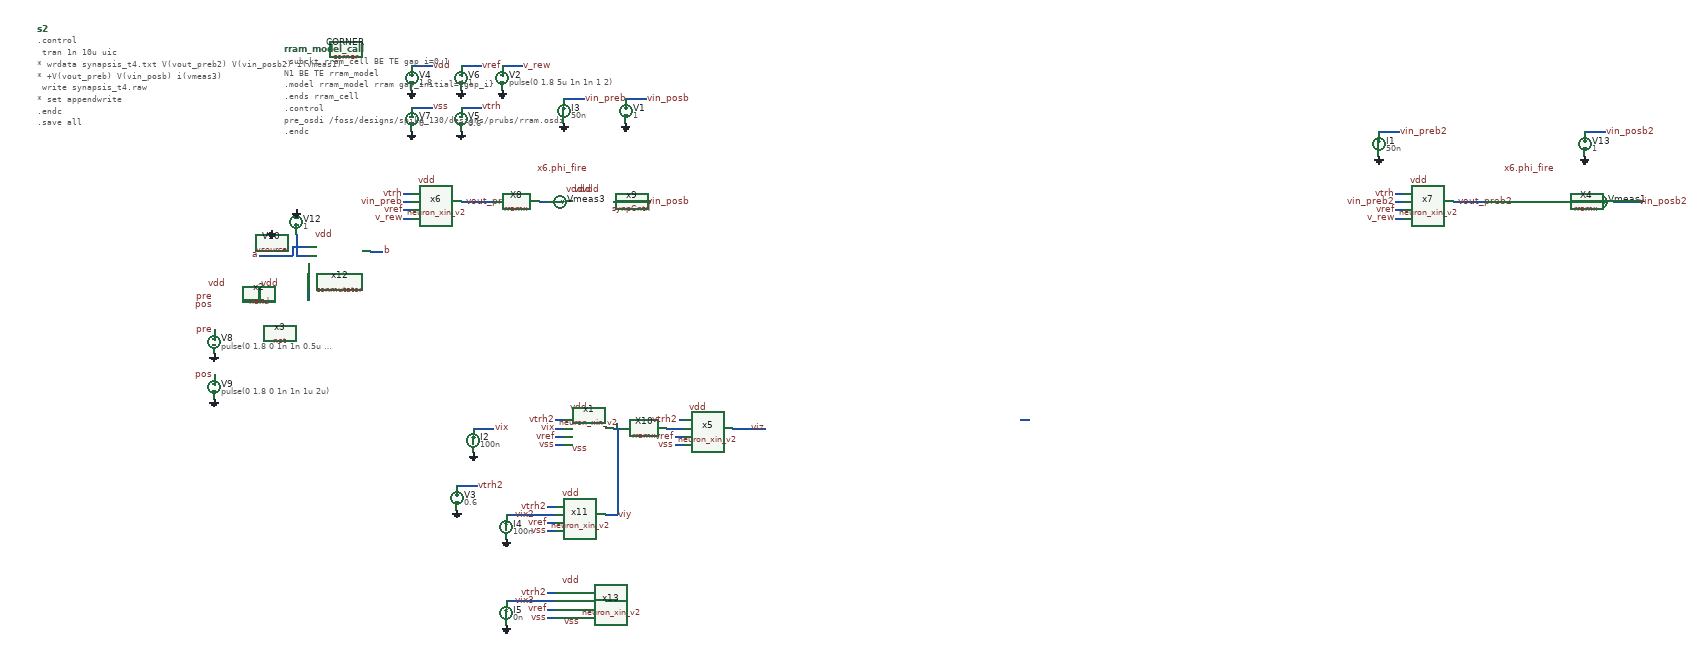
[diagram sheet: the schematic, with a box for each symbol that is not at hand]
v {xschem version=3.4.7 file_version=1.2}
G {}
K {}
V {}
S {}
E {}
B 2 0 -1480 800 -1080 {flags=graph
y1=0
y2=1.8
ypos1=0
ypos2=2
divy=5
subdivy=1
unity=1
x1=3.5072802e-07
x2=4.6602018e-07
divx=5
subdivx=1
xlabmag=1.0
ylabmag=1.0
node="vin_preb
vin_posb
vout_preb
v_rew"
color="4 6 5 10"
dataset=-1
unitx=1
logx=0
logy=0
}
B 2 0 -1080 800 -680 {flags=graph
y2=44000
ypos1=0
ypos2=2
divy=5
subdivy=1
unity=1
x1=3.5072802e-07
x2=4.6602018e-07
divx=5
subdivx=1
xlabmag=1.0
ylabmag=1.0
node="vout_preb net1 - i(vmeas3) /"
color=4
dataset=-1
unitx=1
logx=0
logy=0
y1=31000}
B 2 -1980 -870 -1180 -470 {flags=graph
y2=1.8
ypos1=0
ypos2=2
divy=5
subdivy=1
unity=1
x1=3.5072802e-07
x2=4.6602018e-07
divx=5
subdivx=1
xlabmag=1.0
ylabmag=1.0
node="pre  5 / 0.9 +
pos  5 / 1.4 +
net5 5 / 0.4 +
net4 5 / 0.1 -"
color="4 5 6 8"
dataset=-1
unitx=1
logx=0
logy=0
y1=-0.11}
B 2 -1980 -470 -1180 -70 {flags=graph
y2=2.2
ypos1=0
ypos2=2
divy=5
subdivy=1
unity=1
x1=3.5072802e-07
x2=4.6602018e-07
divx=5
subdivx=1
xlabmag=1.0
ylabmag=1.0
dataset=-1
unitx=1
logx=0
logy=0
y1=0
color="9 4"
node="b
a"}
B 2 -1980 -70 -1180 330 {flags=graph
y2=1.9
ypos1=0
ypos2=2
divy=5
subdivy=1
unity=1
x1=3.5072802e-07
x2=4.6602018e-07
divx=5
subdivx=1
xlabmag=1.0
ylabmag=1.0
dataset=-1
unitx=1
logx=0
logy=0
y1=-0.023
color=9
node=b}
B 2 800 -1080 1600 -680 {flags=graph
y2=1.3e-05
ypos1=0
ypos2=2
divy=5
subdivy=1
unity=1
x1=3.5072802e-07
x2=4.6602018e-07
divx=5
subdivx=1
xlabmag=1.0
ylabmag=1.0
node=i(vmeas3)
color=8
dataset=-1
unitx=1
logx=0
logy=0
y1=-7.9e-06}
B 2 800 -1480 1600 -1080 {flags=graph
y2=0.58
ypos1=0
ypos2=2
divy=5
subdivy=1
unity=1
x1=3.5072802e-07
x2=4.6602018e-07
divx=5
subdivx=1
xlabmag=1.0
ylabmag=1.0
node="vout_preb vin_posb -"
color=9
dataset=-1
unitx=1
logx=0
logy=0
y1=-0.37}
B 2 2440 -1430 3240 -1030 {flags=graph
y1=0
y2=1.8
ypos1=0
ypos2=2
divy=5
subdivy=1
unity=1
x1=3.5072802e-07
x2=4.6602018e-07
divx=5
subdivx=1
xlabmag=1.0
ylabmag=1.0
node="vin_preb2
vin_posb2
vout_preb2
v_rew"
color="4 6 5 10"
dataset=-1
unitx=1
logx=0
logy=0
}
B 2 2440 -1030 3240 -630 {flags=graph
y2=44000
ypos1=0
ypos2=2
divy=5
subdivy=1
unity=1
x1=3.5072802e-07
x2=4.6602018e-07
divx=5
subdivx=1
xlabmag=1.0
ylabmag=1.0
node="vout_preb2 vin_posb2 - i(vmeas1) /"
color=4
dataset=-1
unitx=1
logx=0
logy=0
y1=33000}
B 2 3240 -1030 4040 -630 {flags=graph
ypos1=0
ypos2=2
divy=5
subdivy=1
unity=1
x1=3.5072802e-07
x2=4.6602018e-07
divx=5
subdivx=1
xlabmag=1.0
ylabmag=1.0
node=i(vmeas1)
color=8
dataset=-1
unitx=1
logx=0
logy=0
y1=-9.7e-06
y2=1.7e-05}
B 2 3240 -1430 4040 -1030 {flags=graph
y2=0.55
ypos1=0
ypos2=2
divy=5
subdivy=1
unity=1
x1=3.5072802e-07
x2=4.6602018e-07
divx=5
subdivx=1
xlabmag=1.0
ylabmag=1.0
node="vout_preb2 vin_posb2 -"
color=9
dataset=-1
unitx=1
logx=0
logy=0
y1=-0.37}
B 2 280 -610 1040 -400 {flags=graph
y2=1.5
ypos1=0
ypos2=2
divy=5
subdivy=1
unity=1
x1=3.5072802e-07
x2=4.6602018e-07
divx=5
subdivx=1
xlabmag=1.0
ylabmag=1.0
node="vix
net8"
color="4 6"
dataset=-1
unitx=1
logx=0
logy=0
y1=0.79}
B 2 280 -400 1040 -190 {flags=graph
y2=1.6
ypos1=0
ypos2=2
divy=5
subdivy=1
unity=1
x1=3.5072802e-07
x2=4.6602018e-07
divx=5
subdivx=1
xlabmag=1.0
ylabmag=1.0
node=viz
color=7
dataset=-1
unitx=1
logx=0
logy=0
y1=0.5}
B 2 280 -190 1040 20 {flags=graph
y2=1.8
ypos1=0
ypos2=2
divy=5
subdivy=1
unity=1
x1=3.5072802e-07
x2=4.6602018e-07
divx=5
subdivx=1
xlabmag=1.0
ylabmag=1.0
dataset=-1
unitx=1
logx=0
logy=0
y1=0
color="6 8 4"
node="x5.vmem
x5.phi_fire
vtrh2"}
B 2 1040 -610 1560 -400 {flags=graph
y2=1.5
ypos1=0
ypos2=2
divy=5
subdivy=1
unity=1
x1=3.5072802e-07
x2=4.6602018e-07
divx=5
subdivx=1
xlabmag=1.0
ylabmag=1.0
node=vix
color=4
dataset=-1
unitx=1
logx=0
logy=0
y1=0.6}
B 2 1040 -400 1560 -190 {flags=graph
y2=1.5
ypos1=0
ypos2=2
divy=5
subdivy=1
unity=1
x1=3.5072802e-07
x2=4.6602018e-07
divx=5
subdivx=1
xlabmag=1.0
ylabmag=1.0
node=vix2
color=8
dataset=-1
unitx=1
logx=0
logy=0
y1=0.6}
B 2 1040 -190 1560 20 {flags=graph
y2=1.5
ypos1=0
ypos2=2
divy=5
subdivy=1
unity=1
x1=3.5072802e-07
x2=4.6602018e-07
divx=5
subdivx=1
xlabmag=1.0
ylabmag=1.0
node=vix3
color=10
dataset=-1
unitx=1
logx=0
logy=0
y1=0.6}
P 4 1 3480 -1090 {}
N -640 -1330 -590 -1330 {
lab=vdd}
N -520 -1230 -470 -1230 {
lab=vtrh}
N -520 -1330 -470 -1330 {
lab=vref}
N -640 -1230 -590 -1230 {
lab=vss}
N -660 -980 -640 -980 {
lab=vref}
N -660 -1020 -640 -1020 {
lab=vtrh}
N -660 -960 -640 -960 {
lab=v_rew}
N -660 -1000 -640 -1000 {
lab=vin_preb}
N -130 -1000 -60 -1000 {
lab=vin_posb}
N -520 -1000 -440 -1000 {lab=vout_preb}
N -270 -1250 -220 -1250 {lab=vin_preb}
N -330 -1000 -310 -1000 {lab=#net1}
N -150 -1000 -130 -1000 {lab=vin_posb}
N -120 -1250 -70 -1250 {lab=vin_posb}
N -420 -1330 -370 -1330 {
lab=v_rew}
N -890 -830 -890 -790 {lab=#net2}
N -1010 -870 -930 -870 {lab=a}
N -740 -880 -710 -880 {lab=b}
N -1020 -760 -1000 -760 {lab=#net3}
N -890 -850 -890 -830 {lab=#net2}
N -930 -890 -890 -890 {lab=a}
N -930 -890 -930 -870 {lab=a}
N -920 -870 -890 -870 {lab=#net4}
N -1010 -790 -1010 -760 {lab=#net3}
N -890 -780 -890 -760 {lab=#net2}
N -890 -790 -890 -780 {lab=#net2}
N -920 -920 -920 -870 {lab=#net4}
N 1750 -980 1770 -980 {
lab=vref}
N 1750 -1020 1770 -1020 {
lab=vtrh}
N 1750 -960 1770 -960 {
lab=v_rew}
N 1750 -1000 1770 -1000 {
lab=vin_preb2}
N 2280 -1000 2350 -1000 {
lab=vin_posb2}
N 1890 -1000 1970 -1000 {lab=vout_preb2}
N 2080 -1000 2100 -1000 {lab=#net5}
N 2200 -1000 2220 -1000 {lab=#net5}
N 1710 -1170 1760 -1170 {lab=vin_preb2}
N 2210 -1170 2260 -1170 {lab=vin_posb2}
N 2100 -1000 2200 -1000 {lab=#net5}
N -290 -430 -270 -430 {
lab=vref}
N -290 -470 -270 -470 {
lab=vtrh2}
N -290 -410 -270 -410 {
lab=vss}
N -290 -450 -270 -450 {
lab=vix}
N 0 -430 20 -430 {
lab=vref}
N 840 -470 860 -470 {
lab=#net6}
N 0 -410 20 -410 {
lab=vss}
N 0 -450 20 -450 {
lab=#net7}
N 140 -450 220 -450 {lab=viz}
N -490 -450 -440 -450 {lab=vix}
N -150 -450 -130 -450 {lab=viy}
N -20 -450 -0 -450 {lab=#net7}
N -530 -310 -480 -310 {
lab=vtrh2}
N -310 -220 -290 -220 {
lab=vref}
N -310 -260 -290 -260 {
lab=vtrh2}
N -310 -200 -290 -200 {
lab=vss}
N -310 -240 -290 -240 {
lab=vix2}
N -410 -240 -360 -240 {lab=vix2}
N -360 -240 -310 -240 {lab=vix2}
N -170 -240 -140 -240 {lab=viy}
N -310 -10 -290 -10 {
lab=vref}
N -310 -50 -290 -50 {
lab=vtrh2}
N -310 10 -290 10 {
lab=vss}
N -310 -30 -290 -30 {
lab=vix3}
N -410 -30 -360 -30 {lab=vix3}
N -360 -30 -310 -30 {lab=vix3}
N -170 -30 -140 -30 {lab=#net8}
N 10 -470 20 -470 {lab=vtrh2}
N -140 -450 -140 -240 {lab=viy}
C {devices/code_shown.sym} -1550 -1420 0 0 {name=s2 only_toplevel=false value="
.control
 tran 1n 10u uic


* wrdata synapsis_t4.txt V(vout_preb2) V(vin_posb2) i(vmeas1)
*		       +V(vout_preb) V(vin_posb) i(vmeas3)
 write synapsis_t4.raw
* set appendwrite

.endc
.save all
" }
C {devices/vsource.sym} -640 -1300 0 0 {name=V4 value=1.8}
C {devices/gnd.sym} -640 -1270 0 0 {name=l9 lab=GND}
C {devices/lab_wire.sym} -590 -1330 0 1 {name=p61 sig_type=std_logic lab=vdd}
C {devices/vsource.sym} -520 -1200 0 0 {name=V5 value=0.6}
C {devices/gnd.sym} -520 -1170 0 0 {name=l10 lab=GND}
C {devices/lab_wire.sym} -470 -1230 0 1 {name=p63 sig_type=std_logic lab=vtrh}
C {devices/vsource.sym} -520 -1300 0 0 {name=V6 value=1}
C {devices/gnd.sym} -520 -1270 0 0 {name=l11 lab=GND}
C {devices/lab_wire.sym} -470 -1330 0 1 {name=p64 sig_type=std_logic lab=vref}
C {devices/vsource.sym} -640 -1200 0 0 {name=V7 value=0}
C {devices/gnd.sym} -640 -1170 0 0 {name=l13 lab=GND}
C {devices/lab_wire.sym} -590 -1230 0 1 {name=p72 sig_type=std_logic lab=vss}
C {sky130_fd_pr/corner.sym} -800 -1370 0 0 {name=CORNER only_toplevel=true corner=tt}
C {code.sym} -950 -1370 0 0 {name=rram_model_call only_toplevel=false value=".subckt rram_cell BE TE gap_i=0.1
N1 BE TE rram_model
.model rram_model rram gap_initial=\{gap_i\}
.ends rram_cell

.control
pre_osdi /foss/designs/spike_130/designs/prubs/rram.osdi
.endc"}
C {devices/lab_wire.sym} -660 -980 0 0 {name=p35 sig_type=std_logic lab=vref}
C {devices/lab_wire.sym} -580 -1050 0 0 {name=p37 sig_type=std_logic lab=vdd}
C {devices/lab_wire.sym} -510 -1000 0 1 {name=p38 sig_type=std_logic lab=vout_preb}
C {devices/lab_wire.sym} -660 -1000 0 0 {name=p39 sig_type=std_logic lab=vin_preb}
C {devices/lab_wire.sym} -660 -1020 0 0 {name=p40 sig_type=std_logic lab=vtrh}
C {devices/lab_wire.sym} -580 -950 2 1 {name=p42 sig_type=std_logic lab=vss}
C {devices/lab_wire.sym} -660 -960 0 0 {name=p43 sig_type=std_logic lab=v_rew}
C {devices/ammeter.sym} -280 -1000 3 1 {name=Vmeas3 savecurrent=true spice_ignore=0}
C {devices/isource.sym} -270 -1220 2 0 {name=I3 value=50n}
C {devices/gnd.sym} -270 -1190 0 0 {name=l7 lab=GND}
C {devices/lab_wire.sym} -220 -1250 0 1 {name=p53 sig_type=std_logic lab=vin_preb}
C {/foss/designs/spike_130/designs/memristors/rram_v1/rramx.sym} -380 -1000 0 0 {name=X8
model=rram_cell
spiceprefix=X
gap_i=0.5}
C {devices/lab_wire.sym} -210 -1080 0 0 {name=p55 sig_type=std_logic lab=x6.phi_fire}
C {devices/lab_wire.sym} -200 -1030 1 0 {name=p57 sig_type=std_logic lab=vdd}
C {/foss/designs/spike_130/designs/subcells/core_synpCntrl/synpCntrl.sym} -200 -1000 0 0 {name=x9}
C {devices/lab_wire.sym} -70 -1000 0 1 {name=p21 sig_type=std_logic lab=vin_posb}
C {devices/vsource.sym} -120 -1220 0 0 {name=V1 value=1}
C {devices/gnd.sym} -120 -1190 0 0 {name=l3 lab=GND}
C {devices/lab_wire.sym} -70 -1250 0 1 {name=p32 sig_type=std_logic lab=vin_posb}
C {devices/lab_wire.sym} -180 -1030 1 0 {name=p33 sig_type=std_logic lab=vdd}
C {/foss/designs/spike_130/designs/core_xin_neuron_v2/neuron_xin_v2.sym} -580 -1000 0 0 {name=x6}
C {devices/vsource.sym} -420 -1300 0 0 {name=V2 value="pulse(0 1.8 5u 1n 1n 1 2)"}
C {devices/gnd.sym} -420 -1270 0 0 {name=l1 lab=GND}
C {devices/lab_wire.sym} -370 -1330 0 1 {name=p1 sig_type=std_logic lab=v_rew}
C {launcher.sym} -230 -1370 0 0 {name=h5
descr="load waves" 
tclcommand="xschem raw_read $netlist_dir/synapsis_t4.raw tran"
}
C {devices/lab_wire.sym} -220 -1030 1 0 {name=p2 sig_type=std_logic lab=vdd}
C {devices/lab_wire.sym} -960 -800 0 0 {name=p7 sig_type=std_logic lab=vdd}
C {devices/lab_wire.sym} -1120 -770 0 0 {name=p8 sig_type=std_logic lab=pre}
C {devices/lab_wire.sym} -1120 -750 0 0 {name=p9 sig_type=std_logic lab=pos}
C {devices/lab_wire.sym} -1010 -870 0 0 {name=p10 sig_type=std_logic lab=a}
C {devices/lab_wire.sym} -710 -880 0 1 {name=p11 sig_type=std_logic lab=b}
C {/foss/designs/spike_130/designs/subcells/core_nand/nand.sym} -1080 -750 0 0 {name=x2}
C {devices/lab_wire.sym} -830 -920 0 0 {name=p12 sig_type=std_logic lab=vdd}
C {/foss/designs/spike_130/designs/subcells/core_not/not.sym} -960 -680 0 0 {name=x3}
C {devices/lab_wire.sym} -1090 -800 0 0 {name=p13 sig_type=std_logic lab=vdd}
C {devices/vsource.sym} -1120 -660 0 0 {name=V8 value="pulse(0 1.8 0 1n 1n 0.5u 1u)"}
C {devices/gnd.sym} -1120 -630 0 0 {name=l4 lab=GND}
C {devices/lab_wire.sym} -1120 -690 0 0 {name=p14 sig_type=std_logic lab=pre}
C {devices/vsource.sym} -1120 -550 0 0 {name=V9 value="pulse(0 1.8 0 1n 1n 1u 2u)"}
C {devices/gnd.sym} -1120 -520 0 0 {name=l5 lab=GND}
C {devices/lab_wire.sym} -1120 -580 0 0 {name=p15 sig_type=std_logic lab=pos}
C {launcher.sym} -690 -790 0 0 {name=h1
descr="load waves" 
tclcommand="xschem raw_read $netlist_dir/synapsis_t4.raw tran"
}
C {devices/vsource.sym} -980 -900 2 0 {name=V10 value="pulse(0 1.8 0 0.5u 0.5u 1p 1u)"}
C {devices/gnd.sym} -980 -930 2 0 {name=l6 lab=GND}
C {/foss/designs/spike_130/designs/subcells/core_conmutator/conmutator.sym} -890 -820 0 0 {name=x12}
C {devices/vsource.sym} -920 -950 2 0 {name=V12 value=1}
C {devices/gnd.sym} -920 -980 2 0 {name=l8 lab=GND}
C {devices/lab_wire.sym} 1750 -980 0 0 {name=p16 sig_type=std_logic lab=vref}
C {devices/lab_wire.sym} 1830 -1050 0 0 {name=p17 sig_type=std_logic lab=vdd}
C {devices/lab_wire.sym} 1900 -1000 0 1 {name=p18 sig_type=std_logic lab=vout_preb2}
C {devices/lab_wire.sym} 1750 -1000 0 0 {name=p19 sig_type=std_logic lab=vin_preb2}
C {devices/lab_wire.sym} 1750 -1020 0 0 {name=p20 sig_type=std_logic lab=vtrh}
C {devices/lab_wire.sym} 1830 -950 2 1 {name=p22 sig_type=std_logic lab=vss}
C {devices/lab_wire.sym} 1750 -960 0 0 {name=p23 sig_type=std_logic lab=v_rew}
C {devices/ammeter.sym} 2250 -1000 3 1 {name=Vmeas1 savecurrent=true spice_ignore=0}
C {/foss/designs/spike_130/designs/memristors/rram_v1/rramx.sym} 2030 -1000 0 0 {name=X4
model=rram_cell
spiceprefix=X
gap_i=0.5}
C {devices/lab_wire.sym} 2140 -1080 0 0 {name=p24 sig_type=std_logic lab=x6.phi_fire}
C {devices/lab_wire.sym} 2340 -1000 0 1 {name=p26 sig_type=std_logic lab=vin_posb2}
C {/foss/designs/spike_130/designs/core_xin_neuron_v2/neuron_xin_v2.sym} 1830 -1000 0 0 {name=x7}
C {devices/isource.sym} 1710 -1140 2 0 {name=I1 value=50n}
C {devices/gnd.sym} 1710 -1110 0 0 {name=l14 lab=GND}
C {devices/lab_wire.sym} 1760 -1170 0 1 {name=p29 sig_type=std_logic lab=vin_preb2}
C {devices/vsource.sym} 2210 -1140 0 0 {name=V13 value=1}
C {devices/gnd.sym} 2210 -1110 0 0 {name=l15 lab=GND}
C {devices/lab_wire.sym} 2260 -1170 0 1 {name=p30 sig_type=std_logic lab=vin_posb2}
C {devices/lab_wire.sym} -290 -430 0 0 {name=p3 sig_type=std_logic lab=vref}
C {devices/lab_wire.sym} -210 -500 0 0 {name=p4 sig_type=std_logic lab=vdd}
C {devices/lab_wire.sym} -290 -450 0 0 {name=p6 sig_type=std_logic lab=vix}
C {devices/lab_wire.sym} -290 -470 0 0 {name=p25 sig_type=std_logic lab=vtrh2}
C {devices/lab_wire.sym} -210 -400 2 1 {name=p27 sig_type=std_logic lab=vss}
C {/foss/designs/spike_130/designs/core_xin_neuron_v2/neuron_xin_v2.sym} -210 -450 0 0 {name=x1}
C {devices/lab_wire.sym} 0 -430 0 0 {name=p5 sig_type=std_logic lab=vref}
C {devices/lab_wire.sym} 80 -500 0 0 {name=p31 sig_type=std_logic lab=vdd}
C {devices/lab_wire.sym} 80 -400 2 1 {name=p41 sig_type=std_logic lab=vss}
C {/foss/designs/spike_130/designs/core_xin_neuron_v2/neuron_xin_v2.sym} 80 -450 0 0 {name=x5}
C {devices/isource.sym} -490 -420 2 0 {name=I2 value=100n}
C {devices/gnd.sym} -490 -390 0 0 {name=l2 lab=GND}
C {devices/lab_wire.sym} -440 -450 0 1 {name=p34 sig_type=std_logic lab=vix}
C {devices/lab_wire.sym} 220 -450 0 0 {name=p46 sig_type=std_logic lab=viz}
C {devices/lab_wire.sym} 0 -410 2 1 {name=p28 sig_type=std_logic lab=vss}
C {devices/lab_wire.sym} -290 -410 2 1 {name=p44 sig_type=std_logic lab=vss}
C {launcher.sym} 90 -280 0 0 {name=h2
descr="load waves" 
tclcommand="xschem raw_read $netlist_dir/synapsis_t4.raw tran"
}
C {/foss/designs/spike_130/designs/memristors/rram_v1/rramx.sym} -70 -450 0 0 {name=X10
model=rram_cell
spiceprefix=X
gap_i=0.5}
C {devices/vsource.sym} -530 -280 0 0 {name=V3 value=0.6}
C {devices/gnd.sym} -530 -250 0 0 {name=l12 lab=GND}
C {devices/lab_wire.sym} -480 -310 0 1 {name=p47 sig_type=std_logic lab=vtrh2}
C {devices/lab_wire.sym} -310 -220 0 0 {name=p48 sig_type=std_logic lab=vref}
C {devices/lab_wire.sym} -230 -290 0 0 {name=p49 sig_type=std_logic lab=vdd}
C {devices/lab_wire.sym} -310 -260 0 0 {name=p51 sig_type=std_logic lab=vtrh2}
C {devices/lab_wire.sym} -230 -190 2 1 {name=p52 sig_type=std_logic lab=vss}
C {/foss/designs/spike_130/designs/core_xin_neuron_v2/neuron_xin_v2.sym} -230 -240 0 0 {name=x11}
C {devices/lab_wire.sym} -310 -200 2 1 {name=p54 sig_type=std_logic lab=vss}
C {devices/isource.sym} -410 -210 2 0 {name=I4 value=100n}
C {devices/gnd.sym} -410 -180 0 0 {name=l16 lab=GND}
C {devices/lab_wire.sym} -140 -240 0 1 {name=p50 sig_type=std_logic lab=viy}
C {devices/lab_wire.sym} -310 -10 0 0 {name=p45 sig_type=std_logic lab=vref}
C {devices/lab_wire.sym} -230 -80 0 0 {name=p56 sig_type=std_logic lab=vdd}
C {devices/lab_wire.sym} -310 -50 0 0 {name=p58 sig_type=std_logic lab=vtrh2}
C {devices/lab_wire.sym} -230 20 2 1 {name=p59 sig_type=std_logic lab=vss}
C {/foss/designs/spike_130/designs/core_xin_neuron_v2/neuron_xin_v2.sym} -230 -30 0 0 {name=x13}
C {devices/lab_wire.sym} -310 10 2 1 {name=p60 sig_type=std_logic lab=vss}
C {devices/isource.sym} -410 0 2 0 {name=I5 value=0n}
C {devices/gnd.sym} -410 30 0 0 {name=l17 lab=GND}
C {devices/lab_wire.sym} -390 -240 0 1 {name=p36 sig_type=std_logic lab=vix2}
C {devices/lab_wire.sym} -390 -30 0 1 {name=p62 sig_type=std_logic lab=vix3}
C {devices/lab_wire.sym} 10 -470 0 0 {name=p65 sig_type=std_logic lab=vtrh2}
